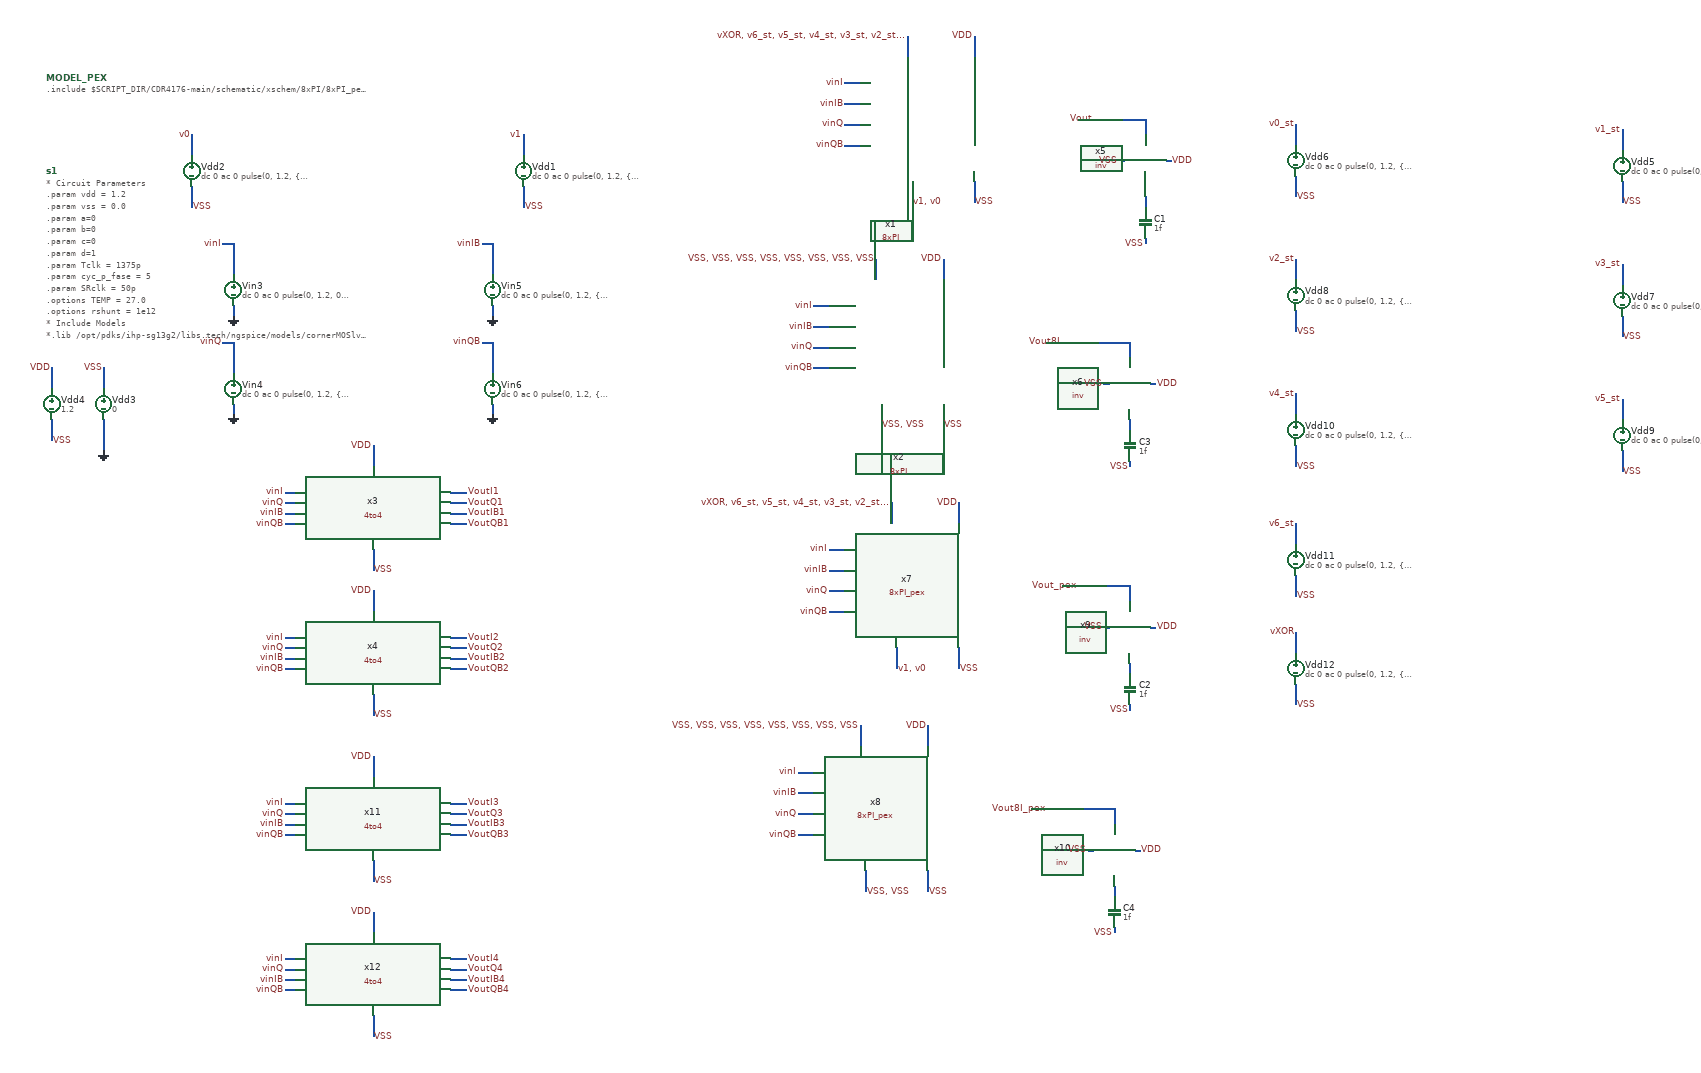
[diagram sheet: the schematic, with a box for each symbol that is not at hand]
v {xschem version=3.4.8RC file_version=1.2}
G {}
K {}
V {}
S {}
F {}
E {}
N 780 -510 780 -470 {lab=v0_st}
N 1410 -500 1410 -460 {lab=v1_st}
N 780 -410 780 -370 {lab=VSS}
N 1410 -400 1410 -360 {lab=VSS}
N 780 -250 780 -210 {lab=v2_st}
N 1410 -240 1410 -200 {lab=v3_st}
N 780 -150 780 -110 {lab=VSS}
N 1410 -140 1410 -100 {lab=VSS}
N 780 10 780 50 {lab=v4_st}
N 1410 20 1410 60 {lab=v5_st}
N 780 110 780 150 {lab=VSS}
N 1410 120 1410 160 {lab=VSS}
N 780 260 780 300 {lab=v6_st}
N 780 360 780 400 {lab=VSS}
N 780 470 780 510 {lab=vXOR}
N 780 570 780 610 {lab=VSS}
N -1270 -160 -1270 -140 {
lab=GND}
N -1270 -280 -1270 -220 {
lab=vinI}
N -1290 -280 -1270 -280 {
lab=vinI}
N -1270 30 -1270 50 {
lab=GND}
N -1270 -90 -1270 -30 {
lab=vinQ}
N -1290 -90 -1270 -90 {
lab=vinQ}
N -770 -160 -770 -140 {
lab=GND}
N -770 -280 -770 -220 {
lab=vinIB}
N -790 -280 -770 -280 {
lab=vinIB}
N -770 -90 -770 -30 {
lab=vinQB}
N -790 -90 -770 -90 {
lab=vinQB}
N -1000 110 -1000 150 {lab=VDD}
N -1170 200 -1150 200 {
lab=vinI}
N -1170 220 -1150 220 {
lab=vinQ}
N -1170 240 -1150 240 {
lab=vinIB}
N -1170 260 -1150 260 {
lab=vinQB}
N -850 200 -820 200 {
lab=VoutI1}
N -850 220 -820 220 {
lab=VoutQ1}
N -850 240 -820 240 {
lab=VoutIB1}
N -850 260 -820 260 {
lab=VoutQB1}
N -770 30 -770 50 {
lab=GND}
N -1620 -40 -1620 0 {lab=VDD}
N -1350 -490 -1350 -450 {lab=v0}
N -710 -490 -710 -450 {lab=v1}
N -1520 60 -1520 120 {
lab=GND}
N -1520 -40 -1520 0 {lab=VSS}
N -1350 -390 -1350 -350 {lab=VSS}
N -710 -390 -710 -350 {lab=VSS}
N -1620 60 -1620 100 {lab=VSS}
N -1000 310 -1000 350 {lab=VSS}
N -90 -590 -60 -590 {
lab=vinI}
N -90 -510 -60 -510 {
lab=vinQ}
N -90 -550 -60 -550 {
lab=vinIB}
N -90 -470 -60 -470 {
lab=vinQB}
N 160 -400 160 -360 {lab=VSS}
N 160 -680 160 -640 {lab=VDD}
N 40 -400 40 -360 {lab="v1, v0"}
N 30 -680 30 -640 {lab="vXOR, v6_st, v5_st, v4_st, v3_st, v2_st, v1_st, v0_st"}
N 360 -520 490 -520 {
lab=Vout}
N -150 -160 -120 -160 {
lab=vinI}
N -150 -80 -120 -80 {
lab=vinQ}
N -150 -120 -120 -120 {
lab=vinIB}
N -150 -40 -120 -40 {
lab=vinQB}
N 100 30 100 70 {lab=VSS}
N 100 -250 100 -210 {lab=VDD}
N -20 30 -20 70 {lab="VSS, VSS"}
N -30 -250 -30 -210 {lab="VSS, VSS, VSS, VSS, VSS, VSS, VSS, VSS"}
N 300 -90 460 -90 {
lab=Vout8I}
N -1000 390 -1000 430 {lab=VDD}
N -1170 480 -1150 480 {
lab=vinI}
N -1170 500 -1150 500 {
lab=vinQ}
N -1170 520 -1150 520 {
lab=vinIB}
N -1170 540 -1150 540 {
lab=vinQB}
N -850 480 -820 480 {
lab=VoutI2}
N -850 500 -820 500 {
lab=VoutQ2}
N -850 520 -820 520 {
lab=VoutIB2}
N -850 540 -820 540 {
lab=VoutQB2}
N -1000 590 -1000 630 {lab=VSS}
N 490 -520 490 -490 {lab=Vout}
N 490 -370 490 -350 {lab=#net1}
N 530 -440 540 -440 {lab=VDD}
N 440 -440 450 -440 {lab=VSS}
N 490 -290 490 -280 {lab=VSS}
N 460 -90 460 -60 {lab=Vout8I}
N 460 60 460 80 {lab=#net2}
N 500 -10 510 -10 {lab=VDD}
N 410 -10 420 -10 {lab=VSS}
N 460 140 460 150 {lab=VSS}
N -1000 710 -1000 750 {lab=VDD}
N -1170 800 -1150 800 {
lab=vinI}
N -1170 820 -1150 820 {
lab=vinQ}
N -1170 840 -1150 840 {
lab=vinIB}
N -1170 860 -1150 860 {
lab=vinQB}
N -850 800 -820 800 {
lab=VoutI3}
N -850 820 -820 820 {
lab=VoutQ3}
N -850 840 -820 840 {
lab=VoutIB3}
N -850 860 -820 860 {
lab=VoutQB3}
N -1000 910 -1000 950 {lab=VSS}
N -1000 1010 -1000 1050 {lab=VDD}
N -1170 1100 -1150 1100 {
lab=vinI}
N -1170 1120 -1150 1120 {
lab=vinQ}
N -1170 1140 -1150 1140 {
lab=vinIB}
N -1170 1160 -1150 1160 {
lab=vinQB}
N -850 1100 -820 1100 {
lab=VoutI4}
N -850 1120 -820 1120 {
lab=VoutQ4}
N -850 1140 -820 1140 {
lab=VoutIB4}
N -850 1160 -820 1160 {
lab=VoutQB4}
N -1000 1210 -1000 1250 {lab=VSS}
N 130 220 130 260 {lab=VDD}
N 330 380 460 380 {lab=Vout_pex}
N 460 380 460 410 {lab=Vout_pex}
N 410 460 420 460 {lab=VSS}
N 500 460 510 460 {lab=VDD}
N 460 530 460 550 {lab=#net3}
N 460 610 460 620 {lab=VSS}
N 130 500 130 540 {lab=VSS}
N 10 500 10 540 {lab="v1, v0" v0}
N -120 430 -90 430 {lab=vinQB}
N -120 390 -90 390 {lab=vinQ}
N -120 350 -90 350 {lab=vinIB}
N -120 310 -90 310 {lab=vinI}
N -0 220 -0 260 {lab="vXOR, v6_st, v5_st, v4_st, v3_st, v2_st, v1_st, v0_st" v6_st, v5_st, v4_st, v3_st, v2_st, v1_st, v0_st}
N 70 650 70 690 {lab=VDD}
N -60 650 -60 690 {lab="VSS, VSS, VSS, VSS, VSS, VSS, VSS, VSS" VSS, VSS, VSS, VSS, VSS, VSS, VSS}
N 270 810 430 810 {lab=Vout8I_pex}
N 430 810 430 840 {lab=Vout8I_pex}
N 380 890 390 890 {lab=VSS}
N 470 890 480 890 {lab=VDD}
N 430 960 430 980 {lab=#net4}
N 430 1040 430 1050 {lab=VSS}
N 70 930 70 970 {lab=VSS}
N -50 930 -50 970 {lab="VSS, VSS" VSS}
N -180 860 -150 860 {lab=vinQB}
N -180 820 -150 820 {lab=vinQ}
N -180 780 -150 780 {lab=vinIB}
N -180 740 -150 740 {lab=vinI}
C {devices/vsource.sym} 1410 -430 0 0 {name=Vdd5 value="dc 0 ac 0 pulse(0, 1.2, \{6*cyc_p_fase*Tclk\}, \{SRclk\}, \{SRclk\}, \{2*cyc_p_fase*Tclk\}, \{8*cyc_p_fase*Tclk\})"}
C {devices/vsource.sym} 780 -440 0 0 {name=Vdd6 value="dc 0 ac 0 pulse(0, 1.2, \{7*cyc_p_fase*Tclk\}, \{SRclk\}, \{SRclk\}, \{cyc_p_fase*Tclk\}, \{8*cyc_p_fase*Tclk\}) "}
C {devices/lab_pin.sym} 780 -510 0 0 {name=p43 sig_type=std_logic lab=v0_st}
C {devices/lab_pin.sym} 1410 -500 0 0 {name=p44 sig_type=std_logic lab=v1_st}
C {devices/lab_pin.sym} 780 -370 2 0 {name=p45 sig_type=std_logic lab=VSS}
C {devices/lab_pin.sym} 1410 -360 2 0 {name=p46 sig_type=std_logic lab=VSS}
C {devices/vsource.sym} 1410 -170 0 0 {name=Vdd7 value="dc 0 ac 0 pulse(0, 1.2, \{4*cyc_p_fase*Tclk\}, \{SRclk\}, \{SRclk\}, \{4*cyc_p_fase*Tclk\}, \{8*cyc_p_fase*Tclk\})"}
C {devices/vsource.sym} 780 -180 0 0 {name=Vdd8 value="dc 0 ac 0 pulse(0, 1.2, \{5*cyc_p_fase*Tclk\}, \{SRclk\}, \{SRclk\}, \{3*cyc_p_fase*Tclk\}, \{8*cyc_p_fase*Tclk\}) "}
C {devices/lab_pin.sym} 780 -250 0 0 {name=p41 sig_type=std_logic lab=v2_st}
C {devices/lab_pin.sym} 1410 -240 0 0 {name=p42 sig_type=std_logic lab=v3_st}
C {devices/lab_pin.sym} 780 -110 2 0 {name=p47 sig_type=std_logic lab=VSS}
C {devices/lab_pin.sym} 1410 -100 2 0 {name=p48 sig_type=std_logic lab=VSS}
C {devices/vsource.sym} 1410 90 0 0 {name=Vdd9 value="dc 0 ac 0 pulse(0, 1.2, \{2*cyc_p_fase*Tclk\}, \{SRclk\}, \{SRclk\}, \{6*cyc_p_fase*Tclk\}, \{8*cyc_p_fase*Tclk\})"}
C {devices/vsource.sym} 780 80 0 0 {name=Vdd10 value="dc 0 ac 0 pulse(0, 1.2, \{3*cyc_p_fase*Tclk\}, \{SRclk\}, \{SRclk\}, \{5*cyc_p_fase*Tclk\}, \{8*cyc_p_fase*Tclk\}) "}
C {devices/lab_pin.sym} 780 10 0 0 {name=p49 sig_type=std_logic lab=v4_st}
C {devices/lab_pin.sym} 1410 20 0 0 {name=p50 sig_type=std_logic lab=v5_st}
C {devices/lab_pin.sym} 780 150 2 0 {name=p51 sig_type=std_logic lab=VSS}
C {devices/lab_pin.sym} 1410 160 2 0 {name=p52 sig_type=std_logic lab=VSS}
C {devices/vsource.sym} 780 330 0 0 {name=Vdd11 value="dc 0 ac 0 pulse(0, 1.2, \{cyc_p_fase*Tclk\}, \{SRclk\}, \{SRclk\}, \{7*cyc_p_fase*Tclk\}, \{8*cyc_p_fase*Tclk\})"}
C {devices/lab_pin.sym} 780 260 0 0 {name=p53 sig_type=std_logic lab=v6_st}
C {devices/lab_pin.sym} 780 400 2 0 {name=p54 sig_type=std_logic lab=VSS}
C {devices/vsource.sym} 780 540 0 0 {name=Vdd12 value="dc 0 ac 0 pulse(0, 1.2, \{40*Tclk\}, \{SRclk\}, \{SRclk\}, \{40*Tclk\}, \{80*Tclk\}) "}
C {devices/lab_pin.sym} 780 470 0 0 {name=p65 sig_type=std_logic lab=vXOR}
C {devices/lab_pin.sym} 780 610 2 0 {name=p66 sig_type=std_logic lab=VSS}
C {devices/gnd.sym} -1270 -140 0 0 {name=l2 lab=GND}
C {devices/vsource.sym} -1270 -190 0 0 {name=Vin3 value="dc 0 ac 0 pulse(0, 1.2, 0, \{SRclk\}, \{SRclk\}, \{Tclk/2-SRclk\}, \{Tclk\}) "}
C {devices/lab_pin.sym} -1290 -280 0 0 {name=p1 sig_type=std_logic lab=vinI}
C {devices/lab_pin.sym} -1290 -90 0 0 {name=p2 sig_type=std_logic lab=vinQ}
C {devices/vsource.sym} -1270 0 0 0 {name=Vin4 value="dc 0 ac 0 pulse(0, 1.2, \{Tclk/4\}, \{SRclk\}, \{SRclk\}, \{Tclk/2-SRclk\}, \{Tclk\}) "}
C {devices/gnd.sym} -770 -140 0 0 {name=l4 lab=GND}
C {devices/vsource.sym} -770 -190 0 0 {name=Vin5 value="dc 0 ac 0 pulse(0, 1.2, \{Tclk/2\}, \{SRclk\}, \{SRclk\}, \{Tclk/2-SRclk\}, \{Tclk\}) "}
C {devices/lab_pin.sym} -790 -280 0 0 {name=p3 sig_type=std_logic lab=vinIB}
C {devices/vsource.sym} -770 0 0 0 {name=Vin6 value="dc 0 ac 0 pulse(0, 1.2, \{3*Tclk/4\}, \{SRclk\}, \{SRclk\}, \{Tclk/2-SRclk\}, \{Tclk\} ) "}
C {devices/lab_pin.sym} -790 -90 0 0 {name=p6 sig_type=std_logic lab=vinQB}
C {devices/lab_pin.sym} -1000 110 0 0 {name=p4 sig_type=std_logic lab=VDD}
C {devices/lab_pin.sym} -1170 200 0 0 {name=p14 sig_type=std_logic lab=vinI}
C {devices/lab_pin.sym} -1170 220 0 0 {name=p8 sig_type=std_logic lab=vinQ}
C {devices/lab_pin.sym} -1170 240 0 0 {name=p17 sig_type=std_logic lab=vinIB}
C {devices/lab_pin.sym} -1170 260 0 0 {name=p18 sig_type=std_logic lab=vinQB}
C {devices/lab_pin.sym} -820 200 2 0 {name=p19 sig_type=std_logic lab=VoutI1}
C {devices/lab_pin.sym} -820 220 2 0 {name=p20 sig_type=std_logic lab=VoutQ1}
C {devices/lab_pin.sym} -820 240 2 0 {name=p21 sig_type=std_logic lab=VoutIB1}
C {devices/lab_pin.sym} -820 260 2 0 {name=p22 sig_type=std_logic lab=VoutQB1}
C {devices/gnd.sym} -1270 50 0 0 {name=l3 lab=GND}
C {devices/gnd.sym} -770 50 0 0 {name=l5 lab=GND}
C {devices/vsource.sym} -1620 30 0 0 {name=Vdd4 value=1.2}
C {devices/lab_pin.sym} -1620 -40 0 0 {name=p26 sig_type=std_logic lab=VDD}
C {devices/vsource.sym} -710 -420 0 0 {name=Vdd1 value="dc 0 ac 0 pulse(0, 1.2, \{16*cyc_p_fase*Tclk\}, \{SRclk\}, \{SRclk\}, \{16cyc_p_fase*Tclk\}, \{32*cyc_p_fase*Tclk\})"}
C {devices/vsource.sym} -1350 -420 0 0 {name=Vdd2 value="dc 0 ac 0 pulse(0, 1.2, \{8*cyc_p_fase*Tclk\}, \{SRclk\}, \{SRclk\}, \{16*cyc_p_fase*Tclk\}, \{32*cyc_p_fase*Tclk\}) "}
C {devices/lab_pin.sym} -1350 -490 0 0 {name=p11 sig_type=std_logic lab=v0}
C {devices/lab_pin.sym} -710 -490 0 0 {name=p10 sig_type=std_logic lab=v1}
C {devices/vsource.sym} -1520 30 0 0 {name=Vdd3 value=0}
C {devices/gnd.sym} -1520 120 0 0 {name=l1 lab=GND}
C {devices/lab_pin.sym} -1520 -40 0 0 {name=p5 sig_type=std_logic lab=VSS}
C {devices/lab_pin.sym} -1350 -350 2 0 {name=p7 sig_type=std_logic lab=VSS}
C {devices/lab_pin.sym} -710 -350 2 0 {name=p9 sig_type=std_logic lab=VSS}
C {devices/lab_pin.sym} -1620 100 2 0 {name=p12 sig_type=std_logic lab=VSS}
C {devices/lab_pin.sym} -1000 350 2 0 {name=p13 sig_type=std_logic lab=VSS}
C {8xPI/8xPI.sym} -80 -380 0 0 {name=x1}
C {devices/lab_pin.sym} -90 -590 0 0 {name=p15 sig_type=std_logic lab=vinI}
C {devices/lab_pin.sym} -90 -510 0 0 {name=p16 sig_type=std_logic lab=vinQ}
C {devices/lab_pin.sym} -90 -550 0 0 {name=p23 sig_type=std_logic lab=vinIB}
C {devices/lab_pin.sym} -90 -470 0 0 {name=p24 sig_type=std_logic lab=vinQB}
C {devices/lab_pin.sym} 160 -360 2 0 {name=p25 sig_type=std_logic lab=VSS}
C {devices/lab_pin.sym} 160 -680 0 0 {name=p27 sig_type=std_logic lab=VDD}
C {devices/lab_pin.sym} 40 -360 2 0 {name=p29 sig_type=std_logic lab="v1, v0"}
C {devices/lab_pin.sym} 30 -680 0 0 {name=p30 sig_type=std_logic lab="vXOR, v6_st, v5_st, v4_st, v3_st, v2_st, v1_st, v0_st"}
C {devices/lab_pin.sym} 390 -520 1 0 {name=p37 sig_type=std_logic lab=Vout}
C {8xPI/8xPI.sym} -140 50 0 0 {name=x2}
C {devices/lab_pin.sym} -150 -160 0 0 {name=p28 sig_type=std_logic lab=vinI}
C {devices/lab_pin.sym} -150 -80 0 0 {name=p31 sig_type=std_logic lab=vinQ}
C {devices/lab_pin.sym} -150 -120 0 0 {name=p32 sig_type=std_logic lab=vinIB}
C {devices/lab_pin.sym} -150 -40 0 0 {name=p33 sig_type=std_logic lab=vinQB}
C {devices/lab_pin.sym} 100 70 2 0 {name=p34 sig_type=std_logic lab=VSS}
C {devices/lab_pin.sym} 100 -250 0 0 {name=p35 sig_type=std_logic lab=VDD}
C {devices/lab_pin.sym} -20 70 2 0 {name=p36 sig_type=std_logic lab="VSS, VSS"}
C {devices/lab_pin.sym} -30 -250 0 0 {name=p38 sig_type=std_logic lab="VSS, VSS, VSS, VSS, VSS, VSS, VSS, VSS"}
C {devices/lab_pin.sym} 330 -90 1 0 {name=p39 sig_type=std_logic lab=Vout8I}
C {netlist_not_shown.sym} -1630 -420 0 0 {name=s1 only_toplevel=false 

value="

* Circuit Parameters
.param vdd = 1.2
.param vss = 0.0
.param a=0
.param b=0
.param c=0
.param d=1
.param Tclk = 1375p
.param cyc_p_fase = 5
.param SRclk = 50p
.options TEMP = 27.0
.options rshunt = 1e12

* Include Models
*.lib /opt/pdks/ihp-sg13g2/libs.tech/ngspice/models/cornerMOSlv.lib mos_tt
*.lib /opt/pdks/ihp-sg13g2/libs.tech/ngspice/models/cornerMOShv.lib mos_tt
*.lib /opt/pdks/ihp-sg13g2/libs.tech/ngspice/models/cornerHBT.lib hbt_typ
*.lib /opt/pdks/ihp-sg13g2/libs.tech/ngspice/models/cornerRES.lib res_typ
.lib cornerMOSlv.lib mos_tt

*         Initial Conditions
* tieh and tiel
.nodeset v(x1.x1[7].x1.tieh)=\{vdd\} v(x1.x1[7].x1.tiel)=0 v(x1.x1[7].x3.tieh)=\{vdd\} v(x1.x1[7].x3.tiel)=0 v(x1.x1[7].x5.tieh)=\{vdd\} v(x1.x1[7].x5.tiel)=0
.nodeset v(x1.x1[6].x1.tieh)=\{vdd\} v(x1.x1[6].x1.tiel)=0 v(x1.x1[6].x3.tieh)=\{vdd\} v(x1.x1[6].x3.tiel)=0 v(x1.x1[6].x5.tieh)=\{vdd\} v(x1.x1[6].x5.tiel)=0
.nodeset v(x1.x1[5].x1.tieh)=\{vdd\} v(x1.x1[5].x1.tiel)=0 v(x1.x1[5].x3.tieh)=\{vdd\} v(x1.x1[5].x3.tiel)=0 v(x1.x1[5].x5.tieh)=\{vdd\} v(x1.x1[5].x5.tiel)=0
.nodeset v(x1.x1[4].x1.tieh)=\{vdd\} v(x1.x1[4].x1.tiel)=0 v(x1.x1[4].x3.tieh)=\{vdd\} v(x1.x1[4].x3.tiel)=0 v(x1.x1[4].x5.tieh)=\{vdd\} v(x1.x1[4].x5.tiel)=0
.nodeset v(x1.x1[3].x1.tieh)=\{vdd\} v(x1.x1[3].x1.tiel)=0 v(x1.x1[3].x3.tieh)=\{vdd\} v(x1.x1[3].x3.tiel)=0 v(x1.x1[3].x5.tieh)=\{vdd\} v(x1.x1[3].x5.tiel)=0
.nodeset v(x1.x1[2].x1.tieh)=\{vdd\} v(x1.x1[2].x1.tiel)=0 v(x1.x1[2].x3.tieh)=\{vdd\} v(x1.x1[2].x3.tiel)=0 v(x1.x1[2].x5.tieh)=\{vdd\} v(x1.x1[2].x5.tiel)=0
.nodeset v(x1.x1[1].x1.tieh)=\{vdd\} v(x1.x1[1].x1.tiel)=0 v(x1.x1[1].x3.tieh)=\{vdd\} v(x1.x1[1].x3.tiel)=0 v(x1.x1[1].x5.tieh)=\{vdd\} v(x1.x1[1].x5.tiel)=0
.nodeset v(x1.x1[0].x1.tieh)=\{vdd\} v(x1.x1[0].x1.tiel)=0 v(x1.x1[0].x3.tieh)=\{vdd\} v(x1.x1[0].x3.tiel)=0 v(x1.x1[0].x5.tieh)=\{vdd\} v(x1.x1[0].x5.tiel)=0
.nodeset v(x2.x1[7].x1.tieh)=\{vdd\} v(x2.x1[7].x1.tiel)=0 v(x2.x1[7].x3.tieh)=\{vdd\} v(x2.x1[7].x3.tiel)=0 v(x2.x1[7].x5.tieh)=\{vdd\} v(x2.x1[7].x5.tiel)=0
.nodeset v(x2.x1[6].x1.tieh)=\{vdd\} v(x2.x1[6].x1.tiel)=0 v(x2.x1[6].x3.tieh)=\{vdd\} v(x2.x1[6].x3.tiel)=0 v(x2.x1[6].x5.tieh)=\{vdd\} v(x2.x1[6].x5.tiel)=0
.nodeset v(x2.x1[5].x1.tieh)=\{vdd\} v(x2.x1[5].x1.tiel)=0 v(x2.x1[5].x3.tieh)=\{vdd\} v(x2.x1[5].x3.tiel)=0 v(x2.x1[5].x5.tieh)=\{vdd\} v(x2.x1[5].x5.tiel)=0
.nodeset v(x2.x1[4].x1.tieh)=\{vdd\} v(x2.x1[4].x1.tiel)=0 v(x2.x1[4].x3.tieh)=\{vdd\} v(x2.x1[4].x3.tiel)=0 v(x2.x1[4].x5.tieh)=\{vdd\} v(x2.x1[4].x5.tiel)=0
.nodeset v(x2.x1[3].x1.tieh)=\{vdd\} v(x2.x1[3].x1.tiel)=0 v(x2.x1[3].x3.tieh)=\{vdd\} v(x2.x1[3].x3.tiel)=0 v(x2.x1[3].x5.tieh)=\{vdd\} v(x2.x1[3].x5.tiel)=0
.nodeset v(x2.x1[2].x1.tieh)=\{vdd\} v(x2.x1[2].x1.tiel)=0 v(x2.x1[2].x3.tieh)=\{vdd\} v(x2.x1[2].x3.tiel)=0 v(x2.x1[2].x5.tieh)=\{vdd\} v(x2.x1[2].x5.tiel)=0
.nodeset v(x2.x1[1].x1.tieh)=\{vdd\} v(x2.x1[1].x1.tiel)=0 v(x2.x1[1].x3.tieh)=\{vdd\} v(x2.x1[1].x3.tiel)=0 v(x2.x1[1].x5.tieh)=\{vdd\} v(x2.x1[1].x5.tiel)=0
.nodeset v(x2.x1[0].x1.tieh)=\{vdd\} v(x2.x1[0].x1.tiel)=0 v(x2.x1[0].x3.tieh)=\{vdd\} v(x2.x1[0].x3.tiel)=0 v(x2.x1[0].x5.tieh)=\{vdd\} v(x2.x1[0].x5.tiel)=0


* OP Parameters & Singals to save
.save V(Vout) V(Vout8I) V(Vout_pex) V(Vout8I_pex) V(vinI) V(vinIB) V(vinQ) V(vinQB) V(VoutI1) V(VoutI2) V(VoutQ1) V(VoutIB1) V(VoutQB1) V(x8.MUX_4_1_1.MUX_2_1_2.inv_PI_1.VOUT) V(x8.MUX_4_1_1.MUX_2_1_2.inv_PI_0.VOUT) V(x1.x1[0].x1.net3) V(x1.x1[0].x1.net4) V(x8.MUX_4_1_1.MUX_2_1_2.tg_custom_14.VSP.t1) V(x8.MUX_4_1_1.MUX_2_1_2.tg_custom_14.VSP.t2) V(x8.MUX_4_1_1.MUX_2_1_2.tg_custom_8.VSP)


*Simulations
.control
*set output_path = tb_linearity_8xpi/
	set ngdebug
	set verbose
	tran 5PS 18NS
	*setplot tran1
	*plot v0 v1+1.5 v0_st+3 v6_st+4.5 Vout+6 Vout8I+7.5 ylabel vout xlabel vin
	set filetype = ascii
        write tran_linearity_termoless_pex.raw 
	*write \{$output_path\}tran_linearity_termoless.raw V(Vout) V(Vout8I) V(vinI) V(VoutI1) V(VoutI2) V(VoutQ1) V(VoutIB1) V(VoutQB1)
.endc
.end"}
C {devices/lab_pin.sym} -1000 390 0 0 {name=p55 sig_type=std_logic lab=VDD}
C {devices/lab_pin.sym} -1170 480 0 0 {name=p56 sig_type=std_logic lab=vinI}
C {devices/lab_pin.sym} -1170 500 0 0 {name=p57 sig_type=std_logic lab=vinQ}
C {devices/lab_pin.sym} -1170 520 0 0 {name=p58 sig_type=std_logic lab=vinIB}
C {devices/lab_pin.sym} -1170 540 0 0 {name=p59 sig_type=std_logic lab=vinQB}
C {devices/lab_pin.sym} -820 480 2 0 {name=p60 sig_type=std_logic lab=VoutI2}
C {devices/lab_pin.sym} -820 500 2 0 {name=p61 sig_type=std_logic lab=VoutQ2}
C {devices/lab_pin.sym} -820 520 2 0 {name=p62 sig_type=std_logic lab=VoutIB2}
C {devices/lab_pin.sym} -820 540 2 0 {name=p63 sig_type=std_logic lab=VoutQB2}
C {devices/lab_pin.sym} -1000 630 2 0 {name=p64 sig_type=std_logic lab=VSS}
C {4to4/4to4.sym} -1000 230 0 0 {name=x3}
C {4to4/4to4.sym} -1000 510 0 0 {name=x4}
C {inv/inv.sym} 350 -530 1 0 {name=x5}
C {capa.sym} 490 -320 0 0 {name=C1
m=1
value=1f
footprint=1206
device="ceramic capacitor"
}
C {devices/lab_pin.sym} 540 -440 2 0 {name=p68 sig_type=std_logic lab=VDD}
C {devices/lab_pin.sym} 440 -440 0 0 {name=p69 sig_type=std_logic lab=VSS}
C {devices/lab_pin.sym} 490 -280 3 0 {name=p70 sig_type=std_logic lab=VSS}
C {inv/inv.sym} 320 -100 1 0 {name=x6}
C {capa.sym} 460 110 0 0 {name=C3
m=1
value=1f
footprint=1206
device="ceramic capacitor"
}
C {devices/lab_pin.sym} 510 -10 2 0 {name=p67 sig_type=std_logic lab=VDD}
C {devices/lab_pin.sym} 410 -10 0 0 {name=p71 sig_type=std_logic lab=VSS}
C {devices/lab_pin.sym} 460 150 3 0 {name=p72 sig_type=std_logic lab=VSS}
C {devices/lab_pin.sym} -120 310 0 0 {name=p40 sig_type=std_logic lab=vinI
}
C {devices/lab_pin.sym} -120 390 0 0 {name=p73 sig_type=std_logic lab=vinQ
}
C {devices/lab_pin.sym} -120 350 0 0 {name=p74 sig_type=std_logic lab=vinIB
}
C {devices/lab_pin.sym} -120 430 0 0 {name=p75 sig_type=std_logic lab=vinQB
}
C {devices/lab_pin.sym} 130 540 2 0 {name=p76 sig_type=std_logic lab=VSS
}
C {devices/lab_pin.sym} 130 220 0 0 {name=p77 sig_type=std_logic lab=VDD
}
C {devices/lab_pin.sym} 10 540 2 0 {name=p78 sig_type=std_logic lab="v1, v0"
}
C {devices/lab_pin.sym} 0 220 0 0 {name=p79 sig_type=std_logic lab="vXOR, v6_st, v5_st, v4_st, v3_st, v2_st, v1_st, v0_st"
}
C {devices/lab_pin.sym} 360 380 1 0 {name=p80 sig_type=std_logic lab=Vout_pex
}
C {devices/lab_pin.sym} -180 740 0 0 {name=p81 sig_type=std_logic lab=vinI
}
C {devices/lab_pin.sym} -180 820 0 0 {name=p82 sig_type=std_logic lab=vinQ
}
C {devices/lab_pin.sym} -180 780 0 0 {name=p83 sig_type=std_logic lab=vinIB
}
C {devices/lab_pin.sym} -180 860 0 0 {name=p84 sig_type=std_logic lab=vinQB
}
C {devices/lab_pin.sym} 70 970 2 0 {name=p85 sig_type=std_logic lab=VSS
}
C {devices/lab_pin.sym} 70 650 0 0 {name=p86 sig_type=std_logic lab=VDD
}
C {devices/lab_pin.sym} -50 970 2 0 {name=p87 sig_type=std_logic lab="VSS, VSS"
}
C {devices/lab_pin.sym} -60 650 0 0 {name=p88 sig_type=std_logic lab="VSS, VSS, VSS, VSS, VSS, VSS, VSS, VSS"
}
C {devices/lab_pin.sym} 300 810 1 0 {name=p89 sig_type=std_logic lab=Vout8I_pex
}
C {inv/inv.sym} 320 370 1 0 {name=x9
}
C {capa.sym} 460 580 0 0 {name=C2
m=1
value=1f
footprint=1206
device="ceramic capacitor"
}
C {devices/lab_pin.sym} 510 460 2 0 {name=p90 sig_type=std_logic lab=VDD
}
C {devices/lab_pin.sym} 410 460 0 0 {name=p91 sig_type=std_logic lab=VSS
}
C {devices/lab_pin.sym} 460 620 3 0 {name=p92 sig_type=std_logic lab=VSS
}
C {inv/inv.sym} 290 800 1 0 {name=x10
}
C {capa.sym} 430 1010 0 0 {name=C4
m=1
value=1f
footprint=1206
device="ceramic capacitor"
}
C {devices/lab_pin.sym} 480 890 2 0 {name=p93 sig_type=std_logic lab=VDD
}
C {devices/lab_pin.sym} 380 890 0 0 {name=p94 sig_type=std_logic lab=VSS
}
C {devices/lab_pin.sym} 430 1050 3 0 {name=p95 sig_type=std_logic lab=VSS
}
C {8xPI/8xPI_pex.sym} 180 460 0 0 {name=x7
}
C {8xPI/8xPI_pex.sym} 120 890 0 0 {name=x8
}
C {devices/lab_pin.sym} -1000 710 0 0 {name=p96 sig_type=std_logic lab=VDD}
C {devices/lab_pin.sym} -1170 800 0 0 {name=p97 sig_type=std_logic lab=vinI}
C {devices/lab_pin.sym} -1170 820 0 0 {name=p98 sig_type=std_logic lab=vinQ}
C {devices/lab_pin.sym} -1170 840 0 0 {name=p99 sig_type=std_logic lab=vinIB}
C {devices/lab_pin.sym} -1170 860 0 0 {name=p100 sig_type=std_logic lab=vinQB}
C {devices/lab_pin.sym} -820 800 2 0 {name=p101 sig_type=std_logic lab=VoutI3}
C {devices/lab_pin.sym} -820 820 2 0 {name=p102 sig_type=std_logic lab=VoutQ3}
C {devices/lab_pin.sym} -820 840 2 0 {name=p103 sig_type=std_logic lab=VoutIB3}
C {devices/lab_pin.sym} -820 860 2 0 {name=p104 sig_type=std_logic lab=VoutQB3}
C {devices/lab_pin.sym} -1000 950 2 0 {name=p105 sig_type=std_logic lab=VSS}
C {4to4/4to4.sym} -1000 830 0 0 {name=x11}
C {devices/lab_pin.sym} -1000 1010 0 0 {name=p106 sig_type=std_logic lab=VDD}
C {devices/lab_pin.sym} -1170 1100 0 0 {name=p107 sig_type=std_logic lab=vinI}
C {devices/lab_pin.sym} -1170 1120 0 0 {name=p108 sig_type=std_logic lab=vinQ}
C {devices/lab_pin.sym} -1170 1140 0 0 {name=p109 sig_type=std_logic lab=vinIB}
C {devices/lab_pin.sym} -1170 1160 0 0 {name=p110 sig_type=std_logic lab=vinQB}
C {devices/lab_pin.sym} -820 1100 2 0 {name=p111 sig_type=std_logic lab=VoutI4}
C {devices/lab_pin.sym} -820 1120 2 0 {name=p112 sig_type=std_logic lab=VoutQ4}
C {devices/lab_pin.sym} -820 1140 2 0 {name=p113 sig_type=std_logic lab=VoutIB4}
C {devices/lab_pin.sym} -820 1160 2 0 {name=p114 sig_type=std_logic lab=VoutQB4}
C {devices/lab_pin.sym} -1000 1250 2 0 {name=p115 sig_type=std_logic lab=VSS}
C {4to4/4to4.sym} -1000 1130 0 0 {name=x12}
C {devices/code_shown.sym} -1630 -600 0 0 {name=MODEL_PEX only_toplevel=true
format="tcleval( @value )"
value="
.include \"$SCRIPT_DIR/CDR4176-main/schematic/xschem/8xPI/8xPI_pex.spice\"
"}
